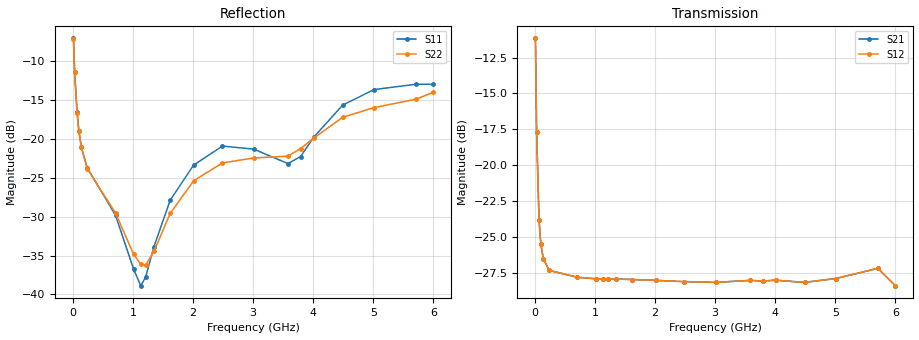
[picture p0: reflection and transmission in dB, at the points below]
! Integrated Device Technology
! Corporate Headquarters
! 6024 Silver Creek Valley Road
! San Jose, CA 95138  USA
! Phone:  1-408-284-8200
! Toll Free:  1-800-223-1366
! Webpage:  http://www.idt.com/
! Timing and RF Division
! 515 Groton Road, Suite 102
! Westford, MA 01886-6024
! Device:  F1951
! Description: 6-bit 0.5 dB Digital Step Attenuator
! Frequency:  100.0 -  4000.00 MHz
! Package:  4x4 mm Thin QFN Plastic Package: 24 pin
! Ports:  2 RF, 6 DC
!  Pin  1  = NC
!  Pin  2  = RF1  =  Port 1
!  Pin  3  = GND
!  Pin  4  = NC
!  Pin  5  = Serial Data Out (SDO)
!  Pin  6  = NC
!  Pin  7  = Reset Bar ( RSTb)
!  Pin  8  = Clock (CLK)
!  Pin  9  = Chip Select Bar (CSb)
!  Pin 10  = NC
!  Pin 11  = Serial Data In (SDI)
!  Pin 12  = NC
!  Pin 13  = NC
!  Pin 14  = VDD
!  Pin 15  = NC
!  Pin 16  = GND
!  Pin 17  = RF2  =  Port 2
!  Pin 18  = NC
!  Pin 19  = GND
!  Pin 20  = GND
!  Pin 21  = GND
!  Pin 22  = GND
!  Pin 23  = GND
!  Pin 24  = GND
! State:  54
! Atten State:  27.0 dB
! Voltage:  +3.30 Volts
! Current:  0.481 mA
! Data:  The device was measured on a F195X evaluation board which has
!  individual transmission lines to the RF pins.  Data was collected
!  de-embedded using a Automatic Fixture Removal [AFR] (Keysight Technologies).
!  The reference plane is the edge of the package pin.
! Misc:  Lot Code  1225BCA
!  Action Tracker AT0399
! Date Measured:  2018-09-13
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# GHz S dB R 50
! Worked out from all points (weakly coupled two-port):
!   600 points, 10 MHz to 6 GHz, reference 50 ohm
!   highest |S21| = -11.16 dB at 10 MHz (marker M1); lowest = -28.4 dB at 6 GHz (marker M2)
!   lowest |S11| = -38.9 dB at 1.13 GHz (marker M3), VSWR 1.02, Z = 48.9 + j0.171 ohm
!   |S11| at or under -10 dB: 22.88 MHz to end of sweep
!   |S22| runs from -36.6 to -7.2 dB; largest |S21 - S12| = 0.00014
!   S11 on the Smith chart (normalised r, x): 10 MHz: 1.74, -1.07; 30 MHz: 1.14, -0.58; 70 MHz: 0.97, -0.30; 1.35 GHz: 0.98, +0.03; 6 GHz: 0.80, +0.37
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0.01  -7.07 -34.0  -11.16 -39.1  -11.16 -39.1  -7.18 -34.0
0.03  -11.36 -61.5  -17.67 -56.9  -17.66 -57.0  -11.44 -61.4
0.07  -16.53 -86.7  -23.79 -47.9  -23.79 -47.9  -16.63 -86.8
0.1  -18.92 -97.5  -25.49 -39.0  -25.49 -38.9  -18.98 -97.6
0.14  -20.99 -107.9  -26.50 -30.9  -26.50 -30.9  -21.07 -107.6
0.24  -23.72 -122.3  -27.33 -21.0  -27.33 -21.0  -23.85 -122.4
0.71  -29.82 -135.2  -27.80 -14.8  -27.80 -14.8  -29.52 -138.2
1.01  -36.72 -155.3  -27.91 -16.4  -27.91 -16.4  -34.82 -152.8
1.13  -38.88 171.2  -27.92 -17.0  -27.92 -17.0  -36.12 -170.5
1.21  -37.81 145.6  -27.92 -17.6  -27.92 -17.7  -36.26 172.9
1.35  -33.86 122.3  -27.93 -18.9  -27.93 -19.0  -34.46 151.0
1.62  -27.89 115.5  -27.96 -21.4  -27.96 -21.4  -29.59 133.3
2.01  -23.37 123.3  -28.02 -25.4  -28.02 -25.4  -25.39 134.5
2.49  -20.92 136.2  -28.11 -30.3  -28.10 -30.3  -23.09 141.7
3.01  -21.32 146.3  -28.16 -35.2  -28.16 -35.2  -22.45 145.1
3.58  -23.17 125.2  -28.02 -40.7  -28.02 -40.7  -22.22 127.9
3.79  -22.28 109.4  -28.06 -42.8  -28.07 -42.7  -21.25 121.1
4.01  -19.77 100.9  -28.01 -44.9  -28.01 -44.9  -19.89 115.8
4.49  -15.66 99.2  -28.16 -49.2  -28.16 -49.2  -17.22 114.0
5.01  -13.66 108.0  -27.89 -51.6  -27.89 -51.6  -15.98 116.4
5.71  -12.97 112.8  -27.18 -63.3  -27.18 -63.3  -14.89 109.1
6  -12.97 106.7  -28.39 -65.2  -28.39 -65.2  -14.01 105.3
